One B-rep face of a CAD part: STEP entity #103.
In plain terms, the toroidal (fillet/blend) face has major radius 12 mm and minor radius 5.5 mm.
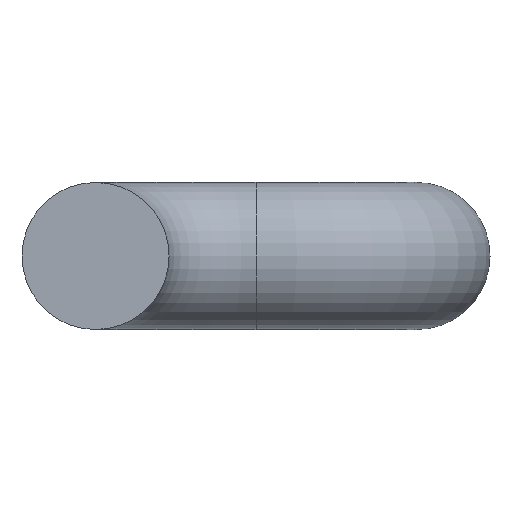
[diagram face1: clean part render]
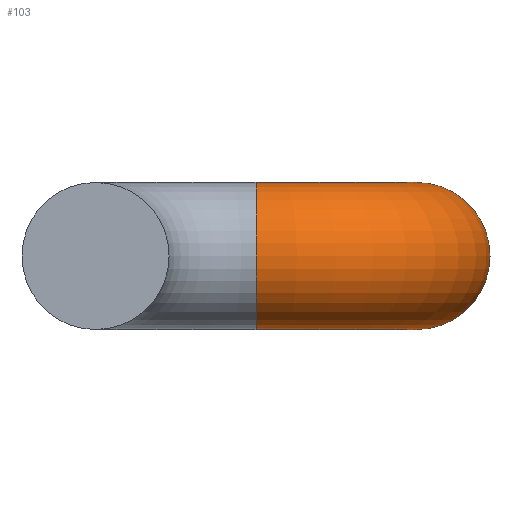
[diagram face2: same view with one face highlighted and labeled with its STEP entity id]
Its self-contained STEP definition (entity closure, numbers rounded to 3 decimals):
#24 = VERTEX_POINT('',#25);
#25 = CARTESIAN_POINT('',(36.5,-16.7,457.1));
#32 = CYLINDRICAL_SURFACE('',#33,5.5);
#33 = AXIS2_PLACEMENT_3D('',#34,#35,#36);
#34 = CARTESIAN_POINT('',(31.,-13.7,457.1));
#35 = DIRECTION('',(0.,-1.,0.));
#36 = DIRECTION('',(1.,0.,0.));
#50 = EDGE_CURVE('',#24,#24,#51,.T.);
#51 = SURFACE_CURVE('',#52,(#57,#64),.PCURVE_S1.);
#52 = CIRCLE('',#53,5.5);
#53 = AXIS2_PLACEMENT_3D('',#54,#55,#56);
#54 = CARTESIAN_POINT('',(31.,-16.7,457.1));
#55 = DIRECTION('',(0.,-1.,0.));
#56 = DIRECTION('',(1.,0.,0.));
#57 = PCURVE('',#32,#58);
#58 = DEFINITIONAL_REPRESENTATION('',(#59),#63);
#59 = LINE('',#60,#61);
#60 = CARTESIAN_POINT('',(0.,3.));
#61 = VECTOR('',#62,1.);
#62 = DIRECTION('',(1.,0.));
#63 = ( GEOMETRIC_REPRESENTATION_CONTEXT(2) 
PARAMETRIC_REPRESENTATION_CONTEXT() REPRESENTATION_CONTEXT('2D SPACE',''
  ) );
#64 = PCURVE('',#65,#70);
#65 = TOROIDAL_SURFACE('',#66,12.,5.5);
#66 = AXIS2_PLACEMENT_3D('',#67,#68,#69);
#67 = CARTESIAN_POINT('',(19.,-16.7,457.1));
#68 = DIRECTION('',(0.,-0.,-1.));
#69 = DIRECTION('',(1.,0.,0.));
#70 = DEFINITIONAL_REPRESENTATION('',(#71),#74);
#71 = B_SPLINE_CURVE_WITH_KNOTS('',1,(#72,#73),.UNSPECIFIED.,.F.,.F.,(2,
    2),(0.,6.283),.PIECEWISE_BEZIER_KNOTS.);
#72 = CARTESIAN_POINT('',(0.,6.283));
#73 = CARTESIAN_POINT('',(0.,0.));
#74 = ( GEOMETRIC_REPRESENTATION_CONTEXT(2) 
PARAMETRIC_REPRESENTATION_CONTEXT() REPRESENTATION_CONTEXT('2D SPACE',''
  ) );
#103 = ADVANCED_FACE('',(#104),#65,.T.);
#104 = FACE_BOUND('',#105,.T.);
#105 = EDGE_LOOP('',(#106,#129,#155,#156));
#106 = ORIENTED_EDGE('',*,*,#107,.T.);
#107 = EDGE_CURVE('',#24,#108,#110,.T.);
#108 = VERTEX_POINT('',#109);
#109 = CARTESIAN_POINT('',(19.,-34.2,457.1));
#110 = SEAM_CURVE('',#111,(#116,#122),.PCURVE_S1.);
#111 = CIRCLE('',#112,17.5);
#112 = AXIS2_PLACEMENT_3D('',#113,#114,#115);
#113 = CARTESIAN_POINT('',(19.,-16.7,457.1));
#114 = DIRECTION('',(0.,-0.,-1.));
#115 = DIRECTION('',(1.,0.,0.));
#116 = PCURVE('',#65,#117);
#117 = DEFINITIONAL_REPRESENTATION('',(#118),#121);
#118 = B_SPLINE_CURVE_WITH_KNOTS('',1,(#119,#120),.UNSPECIFIED.,.F.,.F.,
  (2,2),(0.,1.571),.PIECEWISE_BEZIER_KNOTS.);
#119 = CARTESIAN_POINT('',(0.,0.));
#120 = CARTESIAN_POINT('',(1.571,0.));
#121 = ( GEOMETRIC_REPRESENTATION_CONTEXT(2) 
PARAMETRIC_REPRESENTATION_CONTEXT() REPRESENTATION_CONTEXT('2D SPACE',''
  ) );
#122 = PCURVE('',#65,#123);
#123 = DEFINITIONAL_REPRESENTATION('',(#124),#128);
#124 = LINE('',#125,#126);
#125 = CARTESIAN_POINT('',(0.,6.283));
#126 = VECTOR('',#127,1.);
#127 = DIRECTION('',(1.,0.));
#128 = ( GEOMETRIC_REPRESENTATION_CONTEXT(2) 
PARAMETRIC_REPRESENTATION_CONTEXT() REPRESENTATION_CONTEXT('2D SPACE',''
  ) );
#129 = ORIENTED_EDGE('',*,*,#130,.T.);
#130 = EDGE_CURVE('',#108,#108,#131,.T.);
#131 = SURFACE_CURVE('',#132,(#137,#144),.PCURVE_S1.);
#132 = CIRCLE('',#133,5.5);
#133 = AXIS2_PLACEMENT_3D('',#134,#135,#136);
#134 = CARTESIAN_POINT('',(19.,-28.7,457.1));
#135 = DIRECTION('',(1.,0.,0.));
#136 = DIRECTION('',(0.,-1.,0.));
#137 = PCURVE('',#65,#138);
#138 = DEFINITIONAL_REPRESENTATION('',(#139),#143);
#139 = LINE('',#140,#141);
#140 = CARTESIAN_POINT('',(1.571,0.));
#141 = VECTOR('',#142,1.);
#142 = DIRECTION('',(0.,1.));
#143 = ( GEOMETRIC_REPRESENTATION_CONTEXT(2) 
PARAMETRIC_REPRESENTATION_CONTEXT() REPRESENTATION_CONTEXT('2D SPACE',''
  ) );
#144 = PCURVE('',#145,#150);
#145 = TOROIDAL_SURFACE('',#146,12.,5.5);
#146 = AXIS2_PLACEMENT_3D('',#147,#148,#149);
#147 = CARTESIAN_POINT('',(19.,-40.7,457.1));
#148 = DIRECTION('',(0.,0.,1.));
#149 = DIRECTION('',(0.,1.,0.));
#150 = DEFINITIONAL_REPRESENTATION('',(#151),#154);
#151 = B_SPLINE_CURVE_WITH_KNOTS('',1,(#152,#153),.UNSPECIFIED.,.F.,.F.,
  (2,2),(0.,6.283),.PIECEWISE_BEZIER_KNOTS.);
#152 = CARTESIAN_POINT('',(0.,3.142));
#153 = CARTESIAN_POINT('',(0.,9.425));
#154 = ( GEOMETRIC_REPRESENTATION_CONTEXT(2) 
PARAMETRIC_REPRESENTATION_CONTEXT() REPRESENTATION_CONTEXT('2D SPACE',''
  ) );
#155 = ORIENTED_EDGE('',*,*,#107,.F.);
#156 = ORIENTED_EDGE('',*,*,#50,.T.);
